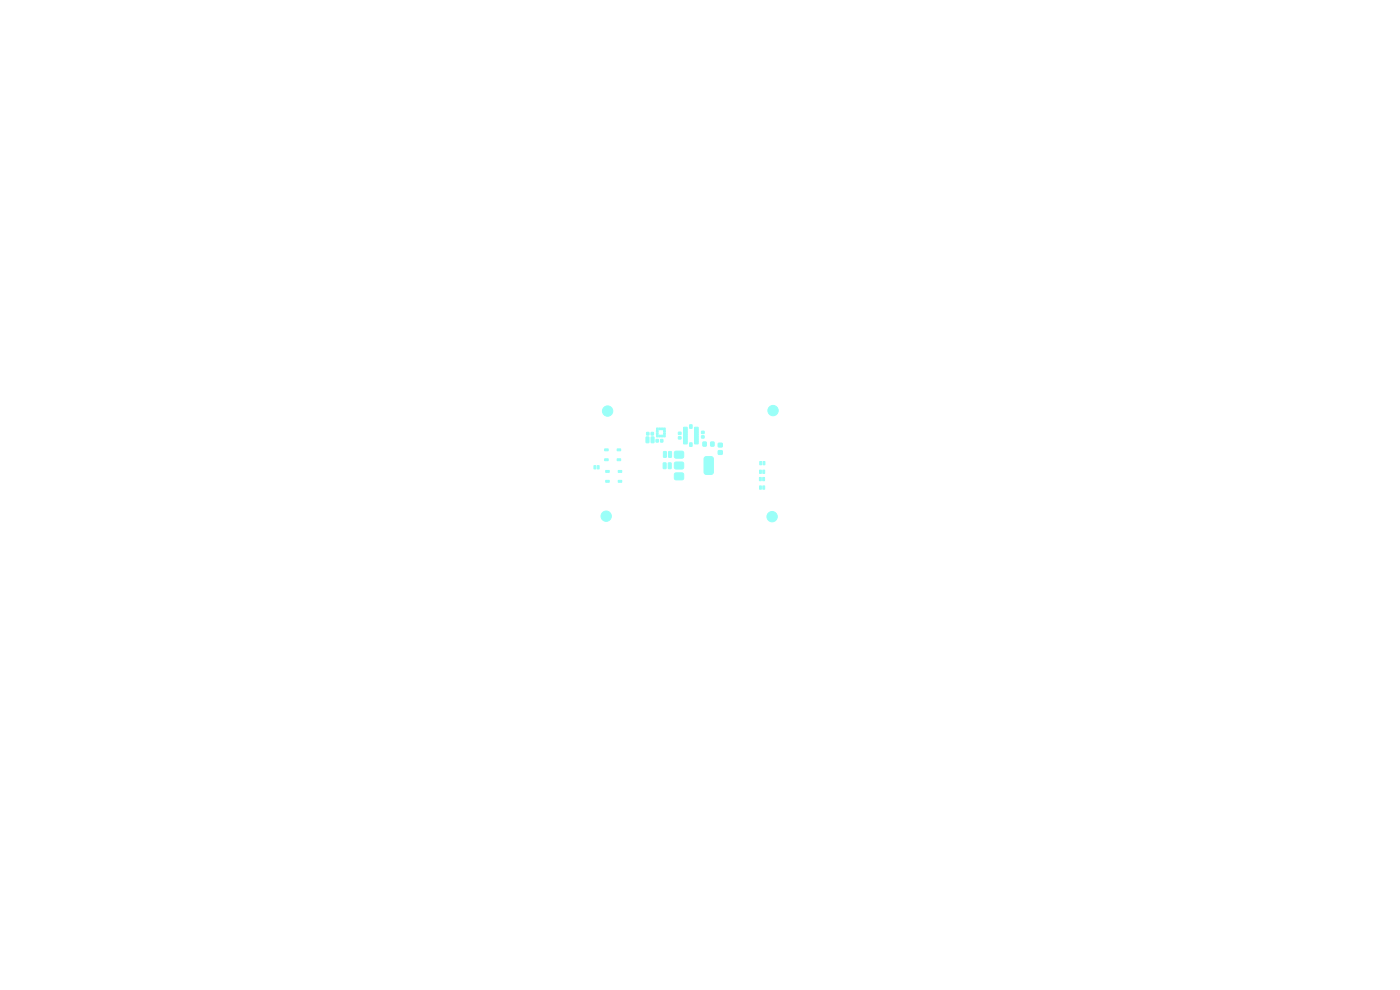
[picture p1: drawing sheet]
<svg xmlns="http://www.w3.org/2000/svg" width="297mm" height="210mm" viewBox="0 0 297 210" stroke-linecap="round" stroke-linejoin="round" font-family="sans-serif">
<g fill="#9afff8" stroke="#9afff8" stroke-width=".21">
<path d="M126 98.8h.4v.7l-.4-.1z"/>
<path d="M126.7 98.8h.4v.7l-.4-.1z"/>
<path d="M161.1 101.3h.4v.7l-.4-.1z"/>
<path d="M161.8 101.3h.4v.7l-.4-.1z"/>
<path d="M161.1 99.7l.4 .1v.6h-.4z"/>
<path d="M161.8 99.7l.4 .1v.6h-.4z"/>
<path d="M161.1 103.1h.4v.7l-.4-.1z"/>
<path d="M161.8 103.1h.4v.7l-.4-.1z"/>
<path d="M161.2 97.9h.4l-.1 .7h-.3z"/>
<path d="M161.9 97.9h.4l-.1 .7h-.3z"/>
<path d="M148.8 92.4h.6v.5h-.6z"/>
<path d="M148.8 91.5h.6v.5h-.6z"/>
<path d="M138.1 91.7h.5v.6h-.5z"/>
<path d="M137.2 91.7h.5v.6h-.5z"/>
<path d="M128.5 99.8h.7v.4h-.7z"/>
<path d="M131.2 99.8h.7v.4h-.7z"/>
<path d="M150.8 93.8h.7v.8h-.7z"/>
<path d="M149.1 93.8h.7v.8h-.7z"/>
<path d="M141.8 98.2l.6 .1-.1 1.1-.5-.1z"/>
<path d="M140.7 98.2l.6 .1-.1 1.1-.5-.1z"/>
<path d="M128.3 97.3h.7v.4h-.7z"/>
<path d="M130.9 97.3h.8v.4h-.8z"/>
<path d="M138.2 92.7l.6 .1-.1 1.1-.6-.1z"/>
<path d="M137.1 92.7l.6 .1-.1 1.1-.6-.1z"/>
<path d="M143.1 100.5l.3-.2 1.5 .1 .2 .3-.1 .9-.3 .2-1.5-.1-.2-.3z"/>
<path d="M143.1 98.2l.3-.2 1.5 .1 .2 .3-.1 .9-.3 .2-1.5-.1-.2-.3z"/>
<path d="M149.5 97l.2-.1 1.2-.1 .4 .3v3l-.2 .5h-1.4l-.3-.2-.1-3z"/>
<path d="M143.2 95.8h1.7l.2 .3-.1 .9-.3 .2-1.5-.1-.2-.3 .1-.8z"/>
<path d="M140.8 92.3h.3v.4h-.3z"/>
<path d="M140.3 92.3h.3v.4h-.3z"/>
<path d="M139.8 92.3h.3v.4h-.3z"/>
<path d="M139.3 92.3h.3v.4h-.3z"/>
<path d="M139.2 91.8h.4v.4h-.4z"/>
<path d="M139.2 91.3h.4v.4h-.4z"/>
<path d="M139.3 90.8h.3v.4h-.3z"/>
<path d="M139.8 90.8h.3v.4h-.3z"/>
<path d="M140.3 90.8h.3v.4h-.3z"/>
<path d="M140.8 90.8h.3v.4h-.3z"/>
<path d="M140.8 91.3h.4v.4h-.4z"/>
<path d="M140.8 91.8h.4v.4h-.4z"/>
<path d="M152.4 95.6h.8v.8h-.8z"/>
<path d="M152.4 94h.8v.8h-.8z"/>
<path d="M143.9 91.7h.6v.5h-.6z"/>
<path d="M143.9 92.6h.6v.5h-.6z"/>
<path d="M139.2 93.2h.5v.6h-.5z"/>
<path d="M140.1 93.2h.5v.6h-.5z"/>
<path d="M128.5 101.9h.7v.4h-.7z"/>
<path d="M131.2 101.9h.7v.4h-.7z"/>
<path d="M128.3 95.2h.7v.4h-.7z"/>
<path d="M130.9 95.2h.8v.4h-.8z"/>
<path d="M141.9 95.8l.6 .1-.1 1.1-.6-.1z"/>
<path d="M140.8 95.8l.6 .1-.1 1.1-.6-.1z"/>
<path d="M145 90.7l.7-.1 .1 .5-.7 .1z"/>
<path d="M145 91.2l.7-.1 .1 .5-.7 .1z"/>
<path d="M145 91.7l.7-.1 .1 .5-.7 .1z"/>
<path d="M145 92.2l.7-.1 .1 .5-.7 .1z"/>
<path d="M145 92.7l.7-.1 .1 .5-.7 .1z"/>
<path d="M145 93.2l.7-.1 .1 .5-.7 .1z"/>
<path d="M145 93.7l.7-.1 .1 .5-.7 .1z"/>
<path d="M146.3 93.9l.5 .1v.7l-.5-.1z"/>
<path d="M147.4 93.7l.7-.1v.5l-.7 .1z"/>
<path d="M147.4 93.2l.7-.1v.5l-.7 .1z"/>
<path d="M147.4 92.7l.7-.1v.5l-.7 .1z"/>
<path d="M147.4 92.2l.7-.1v.5l-.7 .1z"/>
<path d="M147.4 91.7l.7-.1v.5l-.7 .1z"/>
<path d="M147.4 91.2l.7-.1v.5l-.7 .1z"/>
<path d="M147.4 90.7l.7-.1v.5l-.7 .1z"/>
<path d="M146.3 90.1l.5 .1v.7l-.5-.1z"/>
<circle cx="164" cy="87.1" r="1.1"/>
<circle cx="163.8" cy="109.6" r="1.1"/>
<circle cx="128.9" cy="87.2" r="1.1"/>
<circle cx="128.6" cy="109.5" r="1.1"/>
</g>
</svg>
